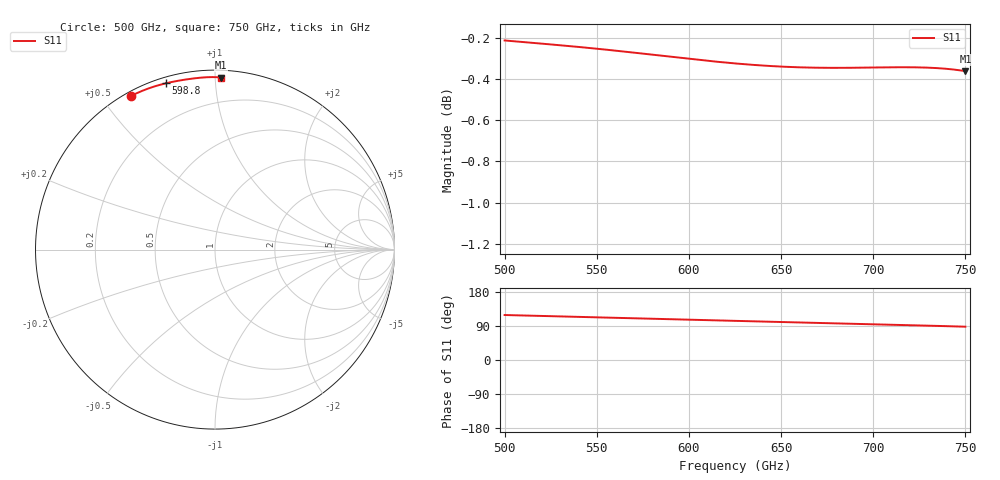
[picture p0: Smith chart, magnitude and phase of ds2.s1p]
!Created with skrf (http://scikit-rf.org).
# GHz S RI R 50.0
!freq ReS11 ImS11
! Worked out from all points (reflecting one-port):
!   401 points, 500 GHz to 750 GHz, reference 50 ohm
!   lowest |S11| = -0.4 dB at 750 GHz (marker M1), VSWR 48.15, Z = 2.16 + j51.8 ohm
!   phase of S11 starts at 119 deg and turns -31 deg over the sweep
!   S11 on the Smith chart (normalised r, x): 500 GHz: 0.02, +0.59; 598.8 GHz: 0.03, +0.75; 750 GHz: 0.04, +1.04
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500  -0.4689 0.8559
501.25  -0.4667 0.857
511.25  -0.4485 0.8657
521.25  -0.4297 0.8742
531.25  -0.4103 0.8825
547.5  -0.3781 0.8951
555  -0.3629 0.9005
562.5  -0.3476 0.9057
570.625  -0.331 0.911
578.125  -0.3156 0.9155
585.625  -0.3002 0.9198
593.75  -0.2836 0.9241
598.75  -0.2734 0.9266
611.25  -0.248 0.9323
625  -0.2205 0.9379
640  -0.1908 0.9432
656.25  -0.1591 0.9482
671.875  -0.1286 0.9525
687.5  -0.098 0.9561
704.375  -0.0641 0.9592
711.875  -0.0487 0.9602
718.75  -0.0343 0.9608
726.875  -0.0169 0.9611
735  0.000999 0.9609
741.875  0.0165 0.9602
748.75  0.0324 0.959
749.375  0.0339 0.9588
750  0.0354 0.9587
